VERSION 5.7 ;
  NOWIREEXTENSIONATPIN ON ;
  DIVIDERCHAR "/" ;
  BUSBITCHARS "[]" ;
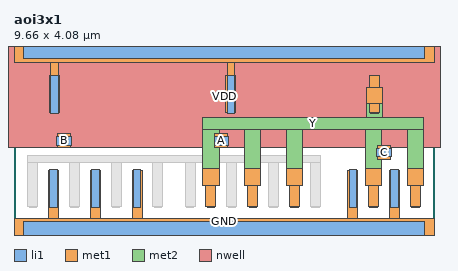
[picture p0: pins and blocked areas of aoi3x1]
MACRO aoi3x1
  CLASS BLOCK ;
  FOREIGN aoi3x1 ;
  ORIGIN 0.000 0.000 ;
  SIZE 9.660 BY 4.080 ;
  PIN B
    ANTENNAGATEAREA 0.882000 ;
    PORT
      LAYER li1 ;
        RECT 0.985 1.930 1.315 2.120 ;
      LAYER met1 ;
        RECT 1.000 1.870 1.300 2.190 ;
    END
  END B
  PIN A
    ANTENNAGATEAREA 0.882000 ;
    PORT
      LAYER li1 ;
        RECT 4.605 1.930 4.935 2.120 ;
      LAYER met1 ;
        RECT 4.620 1.870 4.920 2.190 ;
    END
  END A
  PIN C
    ANTENNAGATEAREA 0.504000 ;
    PORT
      LAYER li1 ;
        RECT 8.345 1.660 8.675 1.850 ;
      LAYER met1 ;
        RECT 8.360 1.600 8.660 1.920 ;
    END
  END C
  PIN Y
    ANTENNADIFFAREA 1.612800 ;
    PORT
      LAYER li1 ;
        RECT 8.205 2.660 8.375 3.540 ;
        RECT 4.445 0.490 4.615 1.370 ;
        RECT 5.405 0.490 5.575 1.370 ;
        RECT 6.365 0.490 6.535 1.370 ;
        RECT 8.185 0.490 8.355 1.370 ;
        RECT 9.145 0.490 9.315 1.370 ;
      LAYER met1 ;
        RECT 8.175 3.260 8.405 3.520 ;
        RECT 8.110 2.880 8.470 3.260 ;
        RECT 8.175 2.680 8.405 2.880 ;
        RECT 4.340 1.010 4.720 1.390 ;
        RECT 5.300 1.010 5.680 1.390 ;
        RECT 6.260 1.010 6.640 1.390 ;
        RECT 8.080 1.010 8.460 1.390 ;
        RECT 9.040 1.010 9.420 1.390 ;
        RECT 4.415 0.510 4.645 1.010 ;
        RECT 5.375 0.510 5.605 1.010 ;
        RECT 6.335 0.510 6.565 1.010 ;
        RECT 8.155 0.510 8.385 1.010 ;
        RECT 9.115 0.510 9.345 1.010 ;
      LAYER met2 ;
        RECT 8.100 2.560 8.480 3.260 ;
        RECT 4.340 2.300 9.420 2.560 ;
        RECT 4.340 1.010 4.720 2.300 ;
        RECT 5.300 1.010 5.680 2.300 ;
        RECT 6.260 1.010 6.640 2.300 ;
        RECT 8.080 1.010 8.460 2.300 ;
        RECT 9.040 1.010 9.420 2.300 ;
    END
  END Y
  PIN VDD
    ANTENNADIFFAREA 3.184200 ;
    PORT
      LAYER nwell ;
        RECT -0.230 1.870 9.890 4.410 ;
      LAYER li1 ;
        RECT 0.210 3.915 9.450 4.245 ;
        RECT 0.845 2.660 1.015 3.540 ;
        RECT 4.905 2.660 5.075 3.540 ;
      LAYER met1 ;
        RECT 0.000 3.840 9.660 4.320 ;
        RECT 0.845 3.520 1.015 3.840 ;
        RECT 4.905 3.520 5.075 3.840 ;
        RECT 0.815 2.680 1.045 3.520 ;
        RECT 4.875 2.680 5.105 3.520 ;
    END
  END VDD
  PIN GND
    ANTENNADIFFAREA 4.066200 ;
    PORT
      LAYER li1 ;
        RECT 0.825 0.490 0.995 1.370 ;
        RECT 1.785 0.490 1.955 1.370 ;
        RECT 2.745 0.490 2.915 1.370 ;
        RECT 7.705 0.490 7.875 1.370 ;
        RECT 8.665 0.490 8.835 1.370 ;
        RECT 0.210 -0.165 9.450 0.165 ;
      LAYER met1 ;
        RECT 0.795 0.240 1.025 1.350 ;
        RECT 1.755 0.240 1.985 1.350 ;
        RECT 2.715 0.240 2.945 1.350 ;
        RECT 7.675 0.240 7.905 1.350 ;
        RECT 8.635 0.240 8.865 1.350 ;
        RECT 0.000 -0.240 9.660 0.240 ;
    END
  END GND
  OBS
      LAYER li1 ;
        RECT 1.285 2.660 1.455 3.540 ;
        RECT 4.465 2.660 4.635 3.540 ;
        RECT 8.645 2.660 8.815 3.540 ;
        RECT 0.345 0.490 0.515 1.370 ;
        RECT 1.305 0.490 1.475 1.370 ;
        RECT 2.265 0.490 2.435 1.370 ;
        RECT 3.225 0.490 3.395 1.370 ;
        RECT 3.965 0.490 4.135 1.370 ;
        RECT 4.925 0.490 5.095 1.370 ;
        RECT 5.885 0.490 6.055 1.370 ;
        RECT 6.845 0.490 7.015 1.370 ;
      LAYER met1 ;
        RECT 1.255 3.200 1.485 3.520 ;
        RECT 2.710 3.200 3.090 3.290 ;
        RECT 4.435 3.200 4.665 3.520 ;
        RECT 1.255 3.000 4.665 3.200 ;
        RECT 1.255 2.680 1.485 3.000 ;
        RECT 2.710 2.910 3.090 3.000 ;
        RECT 4.435 2.680 4.665 3.000 ;
        RECT 8.615 3.200 8.845 3.520 ;
        RECT 9.060 3.200 9.440 3.290 ;
        RECT 8.615 3.000 9.440 3.200 ;
        RECT 8.615 2.680 8.845 3.000 ;
        RECT 9.060 2.910 9.440 3.000 ;
        RECT 0.315 1.540 7.045 1.690 ;
        RECT 0.315 0.510 0.545 1.540 ;
        RECT 1.275 0.510 1.505 1.540 ;
        RECT 2.235 0.510 2.465 1.540 ;
        RECT 3.195 0.510 3.425 1.540 ;
        RECT 3.935 0.510 4.165 1.540 ;
        RECT 4.895 0.510 5.125 1.540 ;
        RECT 5.855 0.510 6.085 1.540 ;
        RECT 6.815 0.510 7.045 1.540 ;
      LAYER met2 ;
        RECT 2.710 3.460 9.440 3.720 ;
        RECT 2.710 2.970 3.090 3.460 ;
        RECT 9.060 2.970 9.440 3.460 ;
  END
END aoi3x1
END LIBRARY

